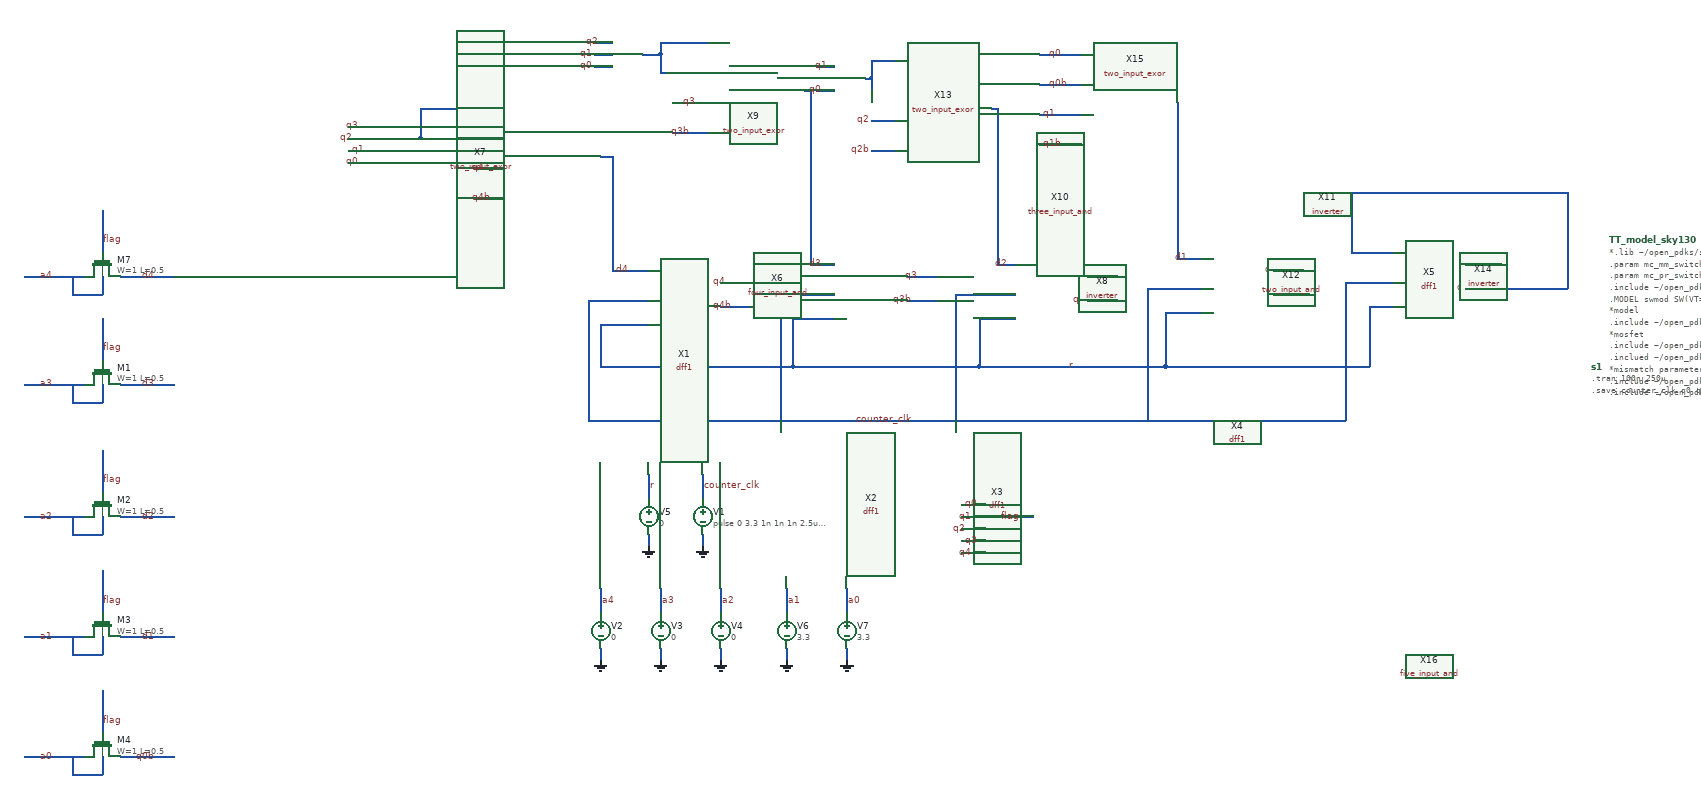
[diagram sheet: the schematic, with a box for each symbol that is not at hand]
v {xschem version=2.9.9 file_version=1.2 }
G {}
K {}
V {}
S {}
E {}
N -1060 160 -1060 180 { lab=GND}
N -1060 60 -1060 100 { lab=r}
N -970 160 -970 180 { lab=GND}
N -970 60 -970 100 { lab=counter_clk}
N -940 -260 -890 -260 { lab=q4}
N -940 -220 -890 -220 { lab=q4b}
N -630 -270 -580 -270 { lab=q3}
N -630 -230 -580 -230 { lab=q3b}
N -330 -270 -280 -270 { lab=q2}
N -330 -230 -280 -230 { lab=q2b}
N -20 -280 30 -280 { lab=q1}
N -20 -240 40 -240 { lab=q1b}
N 300 -290 360 -290 { lab=q0}
N 300 -250 360 -250 { lab=q0b}
N -1140 -230 -1060 -230 { lab=counter_clk}
N -1140 -190 -1060 -190 { lab=r}
N -810 -240 -750 -240 { lab=counter_clk}
N -810 -200 -750 -200 { lab=r}
N -510 -240 -450 -240 { lab=counter_clk}
N -510 -200 -450 -200 { lab=r}
N -200 -250 -140 -250 { lab=counter_clk}
N -200 -210 -140 -210 { lab=r}
N 100 -260 180 -260 { lab=counter_clk}
N -1560 -520 -1520 -520 { lab=q3}
N -1560 -500 -1520 -500 { lab=q2}
N -1560 -480 -1520 -480 { lab=q1}
N -1560 -460 -1520 -460 { lab=q0}
N -1470 -500 -1440 -500 { lab=#net1}
N -1440 -550 -1300 -550 { lab=#net1}
N -1440 -550 -1440 -500 { lab=#net1}
N -1440 -500 -1420 -500 { lab=#net1}
N -1380 -500 -1300 -500 { lab=#net2}
N -1350 -450 -1300 -450 { lab=q4}
N -1350 -400 -1300 -400 { lab=q4b}
N -1140 -470 -1120 -470 { lab=d4}
N -1120 -280 -1060 -280 { lab=d4}
N -1150 -660 -1120 -660 { lab=q2}
N -1150 -640 -1120 -640 { lab=q1}
N -1150 -620 -1120 -620 { lab=q0}
N -1070 -640 -1040 -640 { lab=#net3}
N -1040 -660 -1040 -640 { lab=#net3}
N -1040 -660 -960 -660 { lab=#net3}
N -1040 -640 -1040 -610 { lab=#net3}
N -1040 -610 -1030 -610 { lab=#net3}
N -990 -610 -960 -610 { lab=#net4}
N -1020 -560 -960 -560 { lab=q3}
N -1020 -510 -960 -510 { lab=q3b}
N -800 -580 -790 -580 { lab=d3}
N -790 -290 -750 -290 { lab=d3}
N -780 -620 -750 -620 { lab=q1}
N -780 -580 -750 -580 { lab=q0}
N -700 -600 -690 -600 { lab=#net5}
N -690 -630 -690 -600 { lab=#net5}
N -690 -630 -650 -630 { lab=#net5}
N -690 -600 -690 -580 { lab=#net5}
N -690 -530 -650 -530 { lab=q2}
N -690 -480 -650 -480 { lab=q2b}
N -490 -550 -480 -550 { lab=d2}
N -480 -290 -450 -290 { lab=d2}
N -410 -640 -340 -640 { lab=q0}
N -410 -590 -340 -590 { lab=q0b}
N -410 -540 -340 -540 { lab=q1}
N -410 -490 -340 -490 { lab=q1b}
N -180 -300 -140 -300 { lab=d1}
N 110 -310 180 -310 { lab=q0b}
N 470 -260 470 -250 { lab=q0b}
N 360 -250 470 -250 { lab=q0b}
N -1160 -230 -1140 -230 { lab=counter_clk}
N -1160 -230 -1160 -30 { lab=counter_clk}
N -1160 -30 100 -30 { lab=counter_clk}
N 100 -260 100 -30 { lab=counter_clk}
N -840 -240 -810 -240 { lab=counter_clk}
N -840 -240 -840 -30 { lab=counter_clk}
N -550 -240 -510 -240 { lab=counter_clk}
N -550 -240 -550 -30 { lab=counter_clk}
N -230 -250 -200 -250 { lab=counter_clk}
N -230 -250 -230 -30 { lab=counter_clk}
N -1140 -190 -1140 -120 { lab=r}
N -1140 -120 -820 -120 { lab=r}
N -820 -200 -820 -120 { lab=r}
N -820 -200 -810 -200 { lab=r}
N -820 -120 -510 -120 { lab=r}
N -510 -200 -510 -120 { lab=r}
N -510 -120 -200 -120 { lab=r}
N -200 -210 -200 -120 { lab=r}
N -200 -120 140 -120 { lab=r}
N 140 -220 140 -120 { lab=r}
N 140 -220 180 -220 { lab=r}
N -540 110 -500 110 { lab=q0}
N -540 130 -500 130 { lab=q1}
N -540 150 -500 150 { lab=q2}
N -540 170 -500 170 { lab=q3}
N -540 190 -500 190 { lab=q4}
N -450 130 -420 130 { lab=flag}
N -1120 -470 -1120 -380 { lab=d4}
N -1120 -320 -1120 -280 { lab=d4}
N -790 -580 -790 -420 { lab=d3}
N -790 -360 -790 -290 { lab=d3}
N -480 -350 -480 -290 { lab=d2}
N -480 -550 -480 -410 { lab=d2}
N -180 -560 -180 -430 { lab=d1}
N -180 -370 -180 -300 { lab=d1}
N 110 -410 110 -310 { lab=q0b}
N 110 -410 250 -410 { lab=q0b}
N 310 -410 470 -410 { lab=q0b}
N 470 -410 470 -260 { lab=q0b}
N -1970 -380 -1970 -310 { lab=flag}
N -1970 -270 -1970 -240 { lab=a4}
N -2020 -240 -1970 -240 { lab=a4}
N -2020 -270 -2020 -240 { lab=a4}
N -2100 -270 -2000 -270 { lab=a4}
N -1940 -270 -1850 -270 { lab=d4}
N -1120 -380 -1120 -320 { lab=d4}
N -790 -420 -790 -360 { lab=d3}
N -180 -430 -180 -370 { lab=d1}
N -480 -410 -480 -350 { lab=d2}
N 250 -410 310 -410 { lab=q0b}
N -1140 350 -1140 370 { lab=GND}
N -1140 250 -1140 290 { lab=a4}
N -1970 -200 -1970 -130 { lab=flag}
N -1970 -90 -1970 -60 { lab=a3}
N -2020 -60 -1970 -60 { lab=a3}
N -2020 -90 -2020 -60 { lab=a3}
N -2100 -90 -2000 -90 { lab=a3}
N -1940 -90 -1850 -90 { lab=d3}
N -1970 20 -1970 90 { lab=flag}
N -1970 130 -1970 160 { lab=a2}
N -2020 160 -1970 160 { lab=a2}
N -2020 130 -2020 160 { lab=a2}
N -2100 130 -2000 130 { lab=a2}
N -1940 130 -1850 130 { lab=d2}
N -1970 220 -1970 290 { lab=flag}
N -1970 330 -1970 360 { lab=a1}
N -2020 360 -1970 360 { lab=a1}
N -2020 330 -2020 360 { lab=a1}
N -2100 330 -2000 330 { lab=a1}
N -1940 330 -1850 330 { lab=d1}
N -1970 420 -1970 490 { lab=flag}
N -1970 530 -1970 560 { lab=a0}
N -2020 560 -1970 560 { lab=a0}
N -2020 530 -2020 560 { lab=a0}
N -2100 530 -2000 530 { lab=a0}
N -1940 530 -1850 530 { lab=q0b}
N -1040 350 -1040 370 { lab=GND}
N -1040 250 -1040 290 { lab=a3}
N -940 350 -940 370 { lab=GND}
N -940 250 -940 290 { lab=a2}
N -830 350 -830 370 { lab=GND}
N -830 250 -830 290 { lab=a1}
N -730 350 -730 370 { lab=GND}
N -730 250 -730 290 { lab=a0}
C {devices/code.sym} 540 -330 0 0 {name=TT_model_sky130
format=@value
only_toplevel=true
value="
*.lib ~/open_pdks/sky130/sky130A/libs.tech/ngspice/sky130.lib.spice tt

.param mc_mm_switch=0
.param mc_pr_switch=0

.include ~/open_pdks/sky130/sky130A/libs.tech/ngspice/corners/tt/nonfet.spice
.MODEL swmod SW(VT=1.65 VH=0 RON=1 ROFF=100000000000)

*model
.include ~/open_pdks/sky130/sky130A/libs.tech/ngspice/all.spice


 
*mosfet
.include ~/open_pdks/sky130/sky130A/libs.ref/sky130_fd_pr/spice/sky130_fd_pr__pfet_g5v0d10v5__tt.corner.spice
.inclued ~/open_pdks/sky130/sky130A/libs.ref/sky130_fd_pr/spice/sky130_fd_pr__nfet_g5v0d10v5__tt.corner.spice
*mismatch parameters
.include ~/open_pdks/sky130/sky130A/libs.ref/sky130_fd_pr/spice/sky130_fd_pr__pfet_g5v0d10v5__mismatch.corner.spice
.include ~/open_pdks/sky130/sky130A/libs.ref/sky130_fd_pr/spice/sky130_fd_pr__nfet_g5v0d10v5__mismatch.corner.spice"
}
C {devices/code_shown.sym} 510 -120 0 0 {name=s1 only_toplevel=false value="
.tran 100n 250u
.save counter_clk q0 q1 q2 q3 q4 flag"}
C {devices/vsource.sym} -1060 130 0 0 {name=V5 value=0}
C {devices/gnd.sym} -1060 180 0 0 {name=l26 lab=GND}
C {devices/lab_pin.sym} -1060 80 2 0 {name=l27 sig_type=std_logic lab=r}
C {devices/vsource.sym} -970 130 0 0 {name=V1 value="pulse 0 3.3 1n 1n 1n 2.5u 5u"}
C {devices/gnd.sym} -970 180 0 0 {name=l37 lab=GND}
C {devices/lab_pin.sym} -970 80 2 0 {name=l38 sig_type=std_logic lab=counter_clk}
C {/home/vinodhini/Documents/dff1.sym} -1080 -150 0 0 {name=X1}
C {/home/vinodhini/Documents/dff1.sym} -770 -160 0 0 {name=X2}
C {/home/vinodhini/Documents/dff1.sym} -470 -160 0 0 {name=X3}
C {/home/vinodhini/Documents/dff1.sym} -160 -170 0 0 {name=X4}
C {/home/vinodhini/Documents/dff1.sym} 160 -180 0 0 {name=X5}
C {devices/lab_pin.sym} 320 -290 1 0 {name=l1 sig_type=std_logic lab=q0}
C {devices/lab_pin.sym} 320 -250 1 0 {name=l2 sig_type=std_logic lab=q0b}
C {devices/lab_pin.sym} -10 -280 1 0 {name=l3 sig_type=std_logic lab=q1}
C {devices/lab_pin.sym} 10 -240 1 0 {name=l4 sig_type=std_logic lab=q1b}
C {devices/lab_pin.sym} -320 -270 1 0 {name=l5 sig_type=std_logic lab=q2}
C {devices/lab_pin.sym} -320 -230 1 0 {name=l6 sig_type=std_logic lab=q2b}
C {devices/lab_pin.sym} -610 -270 1 0 {name=l7 sig_type=std_logic lab=q3}
C {devices/lab_pin.sym} -620 -230 1 0 {name=l8 sig_type=std_logic lab=q3b}
C {devices/lab_pin.sym} -930 -260 1 0 {name=l9 sig_type=std_logic lab=q4}
C {devices/lab_pin.sym} -920 -220 1 0 {name=l10 sig_type=std_logic lab=q4b}
C {/home/vinodhini/Documents/four_input_and.symbol} -780 -250 0 0 {name=X6}
C {devices/lab_pin.sym} -1540 -520 1 0 {name=l11 sig_type=std_logic lab=q3}
C {devices/lab_pin.sym} -1550 -500 1 0 {name=l12 sig_type=std_logic lab=q2}
C {devices/lab_pin.sym} -1530 -480 1 0 {name=l13 sig_type=std_logic lab=q1}
C {devices/lab_pin.sym} -1540 -460 1 0 {name=l14 sig_type=std_logic lab=q0}
C {/home/vinodhini/Documents/two_input_exor.sym} -1180 -430 0 0 {name=X7}
C {/home/vinodhini/Documents/inverter.sym} -320 -280 0 0 {name=X8}
C {devices/lab_pin.sym} -1330 -450 1 0 {name=l15 sig_type=std_logic lab=q4}
C {devices/lab_pin.sym} -1320 -400 1 0 {name=l16 sig_type=std_logic lab=q4b}
C {/home/vinodhini/Documents/two_input_exor.sym} -840 -540 0 0 {name=X9}
C {/home/vinodhini/Documents/three_input_and.symbol} -380 -390 0 0 {name=X10}
C {devices/lab_pin.sym} -1140 -660 1 0 {name=l17 sig_type=std_logic lab=q2}
C {devices/lab_pin.sym} -1150 -640 1 0 {name=l18 sig_type=std_logic lab=q1}
C {devices/lab_pin.sym} -1150 -620 0 0 {name=l19 sig_type=std_logic lab=q0}
C {/home/vinodhini/Documents/inverter.sym} 70 -390 0 0 {name=X11}
C {devices/lab_pin.sym} -980 -560 1 0 {name=l20 sig_type=std_logic lab=q3}
C {devices/lab_pin.sym} -990 -510 1 0 {name=l21 sig_type=std_logic lab=q3b}
C {/home/vinodhini/Documents/two_input_and.symbol} -10 -350 0 0 {name=X12}
C {/home/vinodhini/Documents/two_input_exor.sym} -530 -510 0 0 {name=X13}
C {devices/lab_pin.sym} -760 -620 1 0 {name=l22 sig_type=std_logic lab=q1}
C {devices/lab_pin.sym} -770 -580 1 0 {name=l23 sig_type=std_logic lab=q0}
C {/home/vinodhini/Documents/inverter.sym} 410 -360 0 0 {name=X14}
C {devices/lab_pin.sym} -690 -530 0 0 {name=l24 sig_type=std_logic lab=q2}
C {devices/lab_pin.sym} -690 -480 0 0 {name=l25 sig_type=std_logic lab=q2b}
C {/home/vinodhini/Documents/two_input_exor.sym} -220 -520 0 0 {name=X15}
C {devices/lab_pin.sym} -370 -640 1 0 {name=l28 sig_type=std_logic lab=q0}
C {devices/lab_pin.sym} -360 -590 1 0 {name=l29 sig_type=std_logic lab=q0b}
C {devices/lab_pin.sym} -380 -540 1 0 {name=l30 sig_type=std_logic lab=q1}
C {devices/lab_pin.sym} -370 -490 1 0 {name=l31 sig_type=std_logic lab=q1b}
C {devices/lab_pin.sym} -620 -30 1 0 {name=l32 sig_type=std_logic lab=counter_clk}
C {devices/lab_pin.sym} -350 -120 1 0 {name=l33 sig_type=std_logic lab=r}
C {/home/vinodhini/Documents/five_input_and.symbol} 240 380 0 0 {name=X16}
C {devices/lab_pin.sym} -510 110 1 0 {name=l34 sig_type=std_logic lab=q0}
C {devices/lab_pin.sym} -520 130 1 0 {name=l35 sig_type=std_logic lab=q1}
C {devices/lab_pin.sym} -530 150 1 0 {name=l36 sig_type=std_logic lab=q2}
C {devices/lab_pin.sym} -510 170 1 0 {name=l39 sig_type=std_logic lab=q3}
C {devices/lab_pin.sym} -520 190 1 0 {name=l40 sig_type=std_logic lab=q4}
C {devices/lab_pin.sym} -440 130 1 0 {name=l41 sig_type=std_logic lab=flag}
C {devices/lab_pin.sym} -160 -300 1 0 {name=l49 sig_type=std_logic lab=d1}
C {devices/lab_pin.sym} -460 -290 1 0 {name=l50 sig_type=std_logic lab=d2}
C {devices/lab_pin.sym} -770 -290 1 0 {name=l51 sig_type=std_logic lab=d3}
C {devices/lab_pin.sym} -1090 -280 1 0 {name=l52 sig_type=std_logic lab=d4}
C {sky130_fd_pr/nfet_g5v0d10v5.sym} -1970 -290 1 0 {name=M7
L=0.5
W=1
nf=1
mult=1
ad="'int((nf+1)/2) * W/nf * 0.29'" 
pd="'2*int((nf+1)/2) * (W/nf + 0.29)'"
as="'int((nf+2)/2) * W/nf * 0.29'" 
ps="'2*int((nf+2)/2) * (W/nf + 0.29)'"
nrd="'0.29 / W'" nrs="'0.29 / W'"
sa=0 sb=0 sd=0
model=nfet_g5v0d10v5
spiceprefix=X
}
C {devices/lab_pin.sym} -1970 -330 2 0 {name=l54 sig_type=std_logic lab=flag}
C {devices/lab_pin.sym} -2050 -270 1 0 {name=l53 sig_type=std_logic lab=a4}
C {devices/lab_pin.sym} -1880 -270 1 0 {name=l42 sig_type=std_logic lab=d4}
C {devices/vsource.sym} -1140 320 0 0 {name=V2 value=0}
C {devices/gnd.sym} -1140 370 0 0 {name=l43 lab=GND}
C {devices/lab_pin.sym} -1140 270 2 0 {name=l44 sig_type=std_logic lab=a4}
C {sky130_fd_pr/nfet_g5v0d10v5.sym} -1970 -110 1 0 {name=M1
L=0.5
W=1
nf=1
mult=1
ad="'int((nf+1)/2) * W/nf * 0.29'" 
pd="'2*int((nf+1)/2) * (W/nf + 0.29)'"
as="'int((nf+2)/2) * W/nf * 0.29'" 
ps="'2*int((nf+2)/2) * (W/nf + 0.29)'"
nrd="'0.29 / W'" nrs="'0.29 / W'"
sa=0 sb=0 sd=0
model=nfet_g5v0d10v5
spiceprefix=X
}
C {devices/lab_pin.sym} -1970 -150 2 0 {name=l45 sig_type=std_logic lab=flag}
C {devices/lab_pin.sym} -2050 -90 1 0 {name=l46 sig_type=std_logic lab=a3}
C {devices/lab_pin.sym} -1880 -90 1 0 {name=l48 sig_type=std_logic lab=d3}
C {sky130_fd_pr/nfet_g5v0d10v5.sym} -1970 110 1 0 {name=M2
L=0.5
W=1
nf=1
mult=1
ad="'int((nf+1)/2) * W/nf * 0.29'" 
pd="'2*int((nf+1)/2) * (W/nf + 0.29)'"
as="'int((nf+2)/2) * W/nf * 0.29'" 
ps="'2*int((nf+2)/2) * (W/nf + 0.29)'"
nrd="'0.29 / W'" nrs="'0.29 / W'"
sa=0 sb=0 sd=0
model=nfet_g5v0d10v5
spiceprefix=X
}
C {devices/lab_pin.sym} -1970 70 2 0 {name=l55 sig_type=std_logic lab=flag}
C {devices/lab_pin.sym} -2050 130 1 0 {name=l56 sig_type=std_logic lab=a2}
C {devices/lab_pin.sym} -1880 130 1 0 {name=l57 sig_type=std_logic lab=d2}
C {sky130_fd_pr/nfet_g5v0d10v5.sym} -1970 310 1 0 {name=M3
L=0.5
W=1
nf=1
mult=1
ad="'int((nf+1)/2) * W/nf * 0.29'" 
pd="'2*int((nf+1)/2) * (W/nf + 0.29)'"
as="'int((nf+2)/2) * W/nf * 0.29'" 
ps="'2*int((nf+2)/2) * (W/nf + 0.29)'"
nrd="'0.29 / W'" nrs="'0.29 / W'"
sa=0 sb=0 sd=0
model=nfet_g5v0d10v5
spiceprefix=X
}
C {devices/lab_pin.sym} -1970 270 2 0 {name=l58 sig_type=std_logic lab=flag}
C {devices/lab_pin.sym} -2050 330 1 0 {name=l59 sig_type=std_logic lab=a1}
C {devices/lab_pin.sym} -1880 330 1 0 {name=l60 sig_type=std_logic lab=d1}
C {sky130_fd_pr/nfet_g5v0d10v5.sym} -1970 510 1 0 {name=M4
L=0.5
W=1
nf=1
mult=1
ad="'int((nf+1)/2) * W/nf * 0.29'" 
pd="'2*int((nf+1)/2) * (W/nf + 0.29)'"
as="'int((nf+2)/2) * W/nf * 0.29'" 
ps="'2*int((nf+2)/2) * (W/nf + 0.29)'"
nrd="'0.29 / W'" nrs="'0.29 / W'"
sa=0 sb=0 sd=0
model=nfet_g5v0d10v5
spiceprefix=X
}
C {devices/lab_pin.sym} -1970 470 2 0 {name=l61 sig_type=std_logic lab=flag}
C {devices/lab_pin.sym} -2050 530 1 0 {name=l62 sig_type=std_logic lab=a0}
C {devices/lab_pin.sym} -1880 530 1 0 {name=l63 sig_type=std_logic lab=q0b}
C {devices/vsource.sym} -1040 320 0 0 {name=V3 value=0}
C {devices/gnd.sym} -1040 370 0 0 {name=l47 lab=GND}
C {devices/lab_pin.sym} -1040 270 2 0 {name=l64 sig_type=std_logic lab=a3}
C {devices/vsource.sym} -940 320 0 0 {name=V4 value=0}
C {devices/gnd.sym} -940 370 0 0 {name=l65 lab=GND}
C {devices/lab_pin.sym} -940 270 2 0 {name=l66 sig_type=std_logic lab=a2}
C {devices/vsource.sym} -830 320 0 0 {name=V6 value=3.3}
C {devices/gnd.sym} -830 370 0 0 {name=l67 lab=GND}
C {devices/lab_pin.sym} -830 270 2 0 {name=l68 sig_type=std_logic lab=a1}
C {devices/vsource.sym} -730 320 0 0 {name=V7 value=3.3}
C {devices/gnd.sym} -730 370 0 0 {name=l69 lab=GND}
C {devices/lab_pin.sym} -730 270 2 0 {name=l70 sig_type=std_logic lab=a0}
